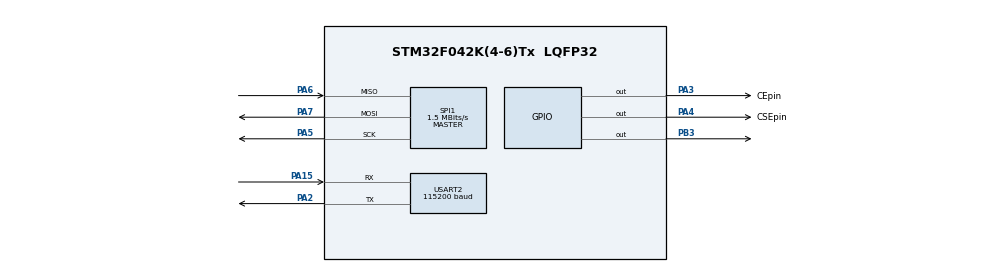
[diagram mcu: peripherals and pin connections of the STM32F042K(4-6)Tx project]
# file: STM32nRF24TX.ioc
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Mcu.Family=STM32F0
PA6.Mode=Full_Duplex_Master
PA7.Mode=Full_Duplex_Master
SPI1.VirtualType=VM_MASTER
USART2.BaudRate=115200
RCC.SYSCLKSource=RCC_SYSCLKSOURCE_HSI48
ProjectManager.StackSize=0x400
ProjectManager.TargetToolchain=SW4STM32
SPI1.Direction=SPI_DIRECTION_2LINES
RCC.HCLKFreq_Value=48000000
SPI1.CalculateBaudRate=1.5 MBits/s
RCC.AHBFreq_Value=48000000
PA5.Signal=SPI1_SCK
board=custom
USART2.VirtualMode-Asynchronous=VM_ASYNC
PA15.Mode=Asynchronous
SPI1.Mode=SPI_MODE_MASTER
SPI1.DataSize=SPI_DATASIZE_8BIT
Mcu.Name=STM32F042K(4-6)Tx
PA2.Signal=USART2_TX
PB3.Signal=GPIO_Output
RCC.SYSCLKFreq_VALUE=48000000
PA4.Signal=GPIO_Output
Mcu.Package=LQFP32
PA6.Signal=SPI1_MISO
PA15.Signal=USART2_RX
ProjectManager.HeapSize=0x200
RCC.APB1TimFreq_Value=48000000
PA2.Mode=Asynchronous
RCC.APB1Freq_Value=48000000
SPI1.BaudRatePrescaler=SPI_BAUDRATEPRESCALER_32
PA4.GPIO_Label=CSEpin
PA3.GPIO_Label=CEpin
PA3.Signal=GPIO_Output
PA7.Signal=SPI1_MOSI
PA5.Mode=Full_Duplex_Master

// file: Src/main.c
/* USER CODE BEGIN Header */
/**
  ******************************************************************************
  * @file           : main.c
  * @brief          : Main program body
  ******************************************************************************
  * @attention
  *
  * <h2><center>&copy; Copyright (c) 2020 STMicroelectronics.
  * All rights reserved.</center></h2>
  *
  * This software component is licensed by ST under BSD 3-Clause license,
  * the "License"; You may not use this file except in compliance with the
  * License. You may obtain a copy of the License at:
  *                        opensource.org/licenses/BSD-3-Clause
  *
  ******************************************************************************
  */
/* USER CODE END Header */

#include "main.h"

/* USER CODE BEGIN Includes */
#include "MY_NRF24.h"				// !! Include NRF24 library (https://www.youtube.com/watch?v=O2dg2Eo7vo8)
/* USER CODE END Includes */

SPI_HandleTypeDef hspi1;

UART_HandleTypeDef huart2;

void SystemClock_Config(void);
static void MX_GPIO_Init(void);
static void MX_SPI1_Init(void);
static void MX_USART2_UART_Init(void);

/* USER CODE BEGIN 0 */
uint64_t TxpipeAddr = 0x11223344AA;
char myTxData[32] = "Hello world!";
/* USER CODE END 0 */

int main(void)
{

  /* MCU Configuration--------------------------------------------------------*/

  /* Reset of all peripherals, Initializes the Flash interface and the Systick. */
  HAL_Init();

  /* Configure the system clock */
  SystemClock_Config();

  /* Initialize all configured peripherals */
  MX_GPIO_Init();
  MX_SPI1_Init();
  MX_USART2_UART_Init();
  /* USER CODE BEGIN 2 */
  NRF24_begin(CEpin_GPIO_Port, CSEpin_Pin, CEpin_Pin, hspi1); // !! Activate NRF24 Library
  nrf24_DebugUART_Init(huart2);								  // !! Init UART Debugger from nRF24 Library

  printRadioSettings();

  // *** TRANSMIT - NO ACK *** //
  NRF24_stopListening();
  NRF24_openWritingPipe(TxpipeAddr);
  NRF24_setAutoAck(false);
  NRF24_setChannel(52);
  NRF24_setPayloadSize(32);
  printRadioSettings();
  /* USER CODE END 2 */

  /* Infinite loop */
  while (1)
  {
	 //printRadioSettings();
	 HAL_GPIO_TogglePin(GPIOB, GPIO_PIN_3);
	 if(NRF24_write(myTxData, 32))
	 {
		 HAL_UART_Transmit(&huart2, (uint8_t *)"\r\nTransmitted Successfully\r\n", strlen("Transmitted Successfully\r\n"),10);
	 }
	 else
	 {
		 HAL_UART_Transmit(&huart2, (uint8_t *)"\r\nTransmission Failed\r\n", strlen("\r\nTransmission Failed\r\n"),10);
	 }
	 HAL_Delay(10000);
  }
}

void SystemClock_Config(void)
{
  RCC_OscInitTypeDef RCC_OscInitStruct = {0};
  RCC_ClkInitTypeDef RCC_ClkInitStruct = {0};

  /** Initializes the CPU, AHB and APB busses clocks
  */
  RCC_OscInitStruct.OscillatorType = RCC_OSCILLATORTYPE_HSI;
  RCC_OscInitStruct.HSIState = RCC_HSI_ON;
  RCC_OscInitStruct.HSICalibrationValue = RCC_HSICALIBRATION_DEFAULT;
  RCC_OscInitStruct.PLL.PLLState = RCC_PLL_NONE;
  if (HAL_RCC_OscConfig(&RCC_OscInitStruct) != HAL_OK)
  {
    Error_Handler();
  }
  /** Initializes the CPU, AHB and APB busses clocks
  */
  RCC_ClkInitStruct.ClockType = RCC_CLOCKTYPE_HCLK|RCC_CLOCKTYPE_SYSCLK
                              |RCC_CLOCKTYPE_PCLK1;
  RCC_ClkInitStruct.SYSCLKSource = RCC_SYSCLKSOURCE_HSI;
  RCC_ClkInitStruct.AHBCLKDivider = RCC_SYSCLK_DIV1;
  RCC_ClkInitStruct.APB1CLKDivider = RCC_HCLK_DIV1;

  if (HAL_RCC_ClockConfig(&RCC_ClkInitStruct, FLASH_LATENCY_0) != HAL_OK)
  {
    Error_Handler();
  }
}

static void MX_SPI1_Init(void)
{

  /* SPI1 parameter configuration*/
  hspi1.Instance = SPI1;
  hspi1.Init.Mode = SPI_MODE_MASTER;
  hspi1.Init.Direction = SPI_DIRECTION_2LINES;
  hspi1.Init.DataSize = SPI_DATASIZE_8BIT;
  hspi1.Init.CLKPolarity = SPI_POLARITY_LOW;
  hspi1.Init.CLKPhase = SPI_PHASE_1EDGE;
  hspi1.Init.NSS = SPI_NSS_SOFT;
  hspi1.Init.BaudRatePrescaler = SPI_BAUDRATEPRESCALER_32;
  hspi1.Init.FirstBit = SPI_FIRSTBIT_MSB;
  hspi1.Init.TIMode = SPI_TIMODE_DISABLE;
  hspi1.Init.CRCCalculation = SPI_CRCCALCULATION_DISABLE;
  hspi1.Init.CRCPolynomial = 7;
  hspi1.Init.CRCLength = SPI_CRC_LENGTH_DATASIZE;
  hspi1.Init.NSSPMode = SPI_NSS_PULSE_ENABLE;
  if (HAL_SPI_Init(&hspi1) != HAL_OK)
  {
    Error_Handler();
  }

}

static void MX_USART2_UART_Init(void)
{

  huart2.Instance = USART2;
  huart2.Init.BaudRate = 115200;
  huart2.Init.WordLength = UART_WORDLENGTH_8B;
  huart2.Init.StopBits = UART_STOPBITS_1;
  huart2.Init.Parity = UART_PARITY_NONE;
  huart2.Init.Mode = UART_MODE_TX_RX;
  huart2.Init.HwFlowCtl = UART_HWCONTROL_NONE;
  huart2.Init.OverSampling = UART_OVERSAMPLING_16;
  huart2.Init.OneBitSampling = UART_ONE_BIT_SAMPLE_DISABLE;
  huart2.AdvancedInit.AdvFeatureInit = UART_ADVFEATURE_NO_INIT;
  if (HAL_UART_Init(&huart2) != HAL_OK)
  {
    Error_Handler();
  }

}

static void MX_GPIO_Init(void)
{
  GPIO_InitTypeDef GPIO_InitStruct = {0};

  /* GPIO Ports Clock Enable */
  __HAL_RCC_GPIOA_CLK_ENABLE();
  __HAL_RCC_GPIOB_CLK_ENABLE();

  /*Configure GPIO pin Output Level */
  HAL_GPIO_WritePin(GPIOA, CEpin_Pin|CSEpin_Pin, GPIO_PIN_RESET);

  /*Configure GPIO pin Output Level */
  HAL_GPIO_WritePin(GPIOB, GPIO_PIN_3, GPIO_PIN_RESET);

  /*Configure GPIO pins : CEpin_Pin CSEpin_Pin */
  GPIO_InitStruct.Pin = CEpin_Pin|CSEpin_Pin;
  GPIO_InitStruct.Mode = GPIO_MODE_OUTPUT_PP;
  GPIO_InitStruct.Pull = GPIO_NOPULL;
  GPIO_InitStruct.Speed = GPIO_SPEED_FREQ_LOW;
  HAL_GPIO_Init(GPIOA, &GPIO_InitStruct);

  /*Configure GPIO pin : PB3 */
  GPIO_InitStruct.Pin = GPIO_PIN_3;
  GPIO_InitStruct.Mode = GPIO_MODE_OUTPUT_PP;
  GPIO_InitStruct.Pull = GPIO_NOPULL;
  GPIO_InitStruct.Speed = GPIO_SPEED_FREQ_LOW;
  HAL_GPIO_Init(GPIOB, &GPIO_InitStruct);

}

void Error_Handler(void)
{
}

/************************ (C) COPYRIGHT STMicroelectronics *****END OF FILE****/
